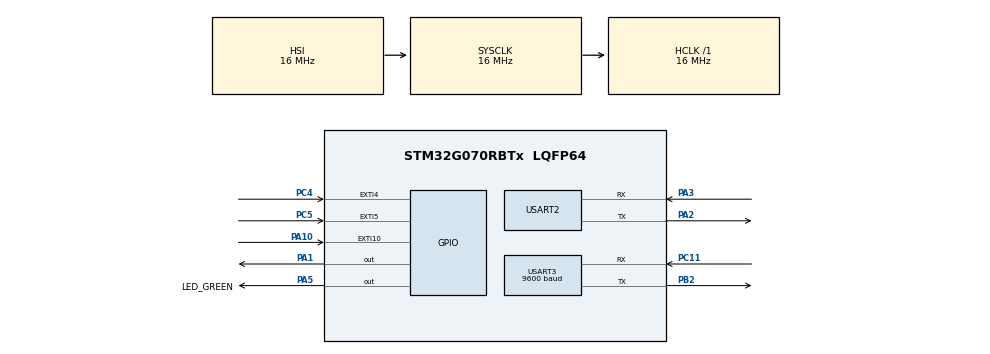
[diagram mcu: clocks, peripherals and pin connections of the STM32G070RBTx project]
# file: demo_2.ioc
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Mcu.Family=STM32G0
Mcu.Name=STM32G070RBTx
Mcu.Package=LQFP64
NVIC.EXTI4_15_IRQn=true\:0\:0\:false\:false\:true\:true\:true
PA1.Signal=GPIO_Output
PA10.GPIO_ModeDefaultEXTI=GPIO_MODE_IT_RISING_FALLING
PA10.GPIO_PuPd=GPIO_PULLUP
PA10.Signal=GPXTI10
PA13.GPIO_Label=TMS
PA13.Mode=Serial_Wire
PA13.Signal=SYS_SWDIO
PA14-BOOT0.GPIO_Label=TCK
PA14-BOOT0.Mode=Serial_Wire
PA14-BOOT0.Signal=SYS_SWCLK
PA2.GPIO_PuPd=GPIO_PULLUP
PA2.Mode=Asynchronous
PA2.Signal=USART2_TX
PA3.GPIO_PuPd=GPIO_PULLUP
PA3.Mode=Asynchronous
PA3.Signal=USART2_RX
PA5.GPIO_Label=LED_GREEN
PA5.GPIO_Speed=GPIO_SPEED_FREQ_HIGH
PA5.Signal=GPIO_Output
PB2.Mode=Asynchronous
PB2.Signal=USART3_TX
PC11.Mode=Asynchronous
PC11.Signal=USART3_RX
PC13.Mode=SYS_WakeUp1
PC13.Signal=SYS_WKUP2
PC14-OSC32_IN\ (PC14).Mode=LSE-External-Oscillator
PC14-OSC32_IN\ (PC14).Signal=RCC_OSC32_IN
PC15-OSC32_OUT\ (PC15).Mode=LSE-External-Oscillator
PC15-OSC32_OUT\ (PC15).Signal=RCC_OSC32_OUT
PC4.GPIO_ModeDefaultEXTI=GPIO_MODE_IT_FALLING
PC4.GPIO_PuPd=GPIO_PULLUP
PC4.Signal=GPXTI4
PC5.GPIO_ModeDefaultEXTI=GPIO_MODE_IT_RISING_FALLING
PC5.GPIO_PuPd=GPIO_PULLUP
PC5.Signal=GPXTI5
PF0-OSC_IN\ (PF0).GPIO_Label=MCO
PF0-OSC_IN\ (PF0).Mode=HSE-External-Clock-Source
PF0-OSC_IN\ (PF0).Signal=RCC_OSC_IN
ProjectManager.HeapSize=0x200
ProjectManager.StackSize=0x400
ProjectManager.TargetToolchain=STM32CubeIDE
RCC.AHBFreq_Value=16000000
RCC.CortexFreq_Value=16000000
RCC.EXTERNAL_CLOCK_VALUE=12288000
RCC.HCLKFreq_Value=16000000
RCC.HSE_VALUE=8000000
RCC.HSI_VALUE=16000000
RCC.SYSCLKFreq_VALUE=16000000
RCC.VCOOutputFreq_Value=128000000
USART2.VirtualMode-Asynchronous=VM_ASYNC
USART2.WordLength=WORDLENGTH_8B
USART3.BaudRate=9600
USART3.VirtualMode-Asynchronous=VM_ASYNC
VP_SYS_VS_DBSignals.Mode=DisableDeadBatterySignals
board=NUCLEO-G070RB

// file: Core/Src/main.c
/* USER CODE BEGIN Header */
/**
  ******************************************************************************
  * @file           : main.c
  * @brief          : Main program body
  ******************************************************************************
  * @attention
  *
  * <h2><center>&copy; Copyright (c) 2020 STMicroelectronics.
  * All rights reserved.</center></h2>
  *
  * This software component is licensed by ST under BSD 3-Clause license,
  * the "License"; You may not use this file except in compliance with the
  * License. You may obtain a copy of the License at:
  *                        opensource.org/licenses/BSD-3-Clause
  *
  ******************************************************************************
  */
/* USER CODE END Header */
#include "main.h"

/* USER CODE BEGIN Includes */
#include "stdio.h"
#include "string.h"
/* USER CODE END Includes */

UART_HandleTypeDef huart2;
UART_HandleTypeDef huart3;

void SystemClock_Config(void);
static void MX_GPIO_Init(void);
static void MX_USART2_UART_Init(void);
static void MX_USART3_UART_Init(void);

int main(void)
{

  /* MCU Configuration--------------------------------------------------------*/

  /* Reset of all peripherals, Initializes the Flash interface and the Systick. */
  HAL_Init();

  /* Configure the system clock */
  SystemClock_Config();

  /* Initialize all configured peripherals */
  MX_GPIO_Init();
  MX_USART2_UART_Init();
  MX_USART3_UART_Init();
  /* USER CODE BEGIN 2 */
  char *msg = "Hello world!\r\n";
  char *Llow = "0";
  char *Lhigh = "75\r\n";

  /* USER CODE END 2 */

  /* Infinite loop */
  /* USER CODE BEGIN WHILE */
  while (1)
  {

//	  if (HAL_GPIO_ReadPin(GPIOB, GPIO_PIN_0)==0){
//		  HAL_UART_Transmit(&huart2, (uint8_t*)Llow, strlen(Llow), 1);
//		  HAL_Delay(100);
//	  }
//	  else if (HAL_GPIO_ReadPin(GPIOB, GPIO_PIN_0)==1){
//		  HAL_UART_Transmit(&huart2, (uint8_t*)Lhigh, strlen(Lhigh), 1);
//		  HAL_Delay(100);
//	  }

    /* USER CODE END WHILE */

  }
}

void SystemClock_Config(void)
{
  RCC_OscInitTypeDef RCC_OscInitStruct = {0};
  RCC_ClkInitTypeDef RCC_ClkInitStruct = {0};
  RCC_PeriphCLKInitTypeDef PeriphClkInit = {0};

  /** Configure the main internal regulator output voltage
  */
  HAL_PWREx_ControlVoltageScaling(PWR_REGULATOR_VOLTAGE_SCALE1);
  /** Initializes the RCC Oscillators according to the specified parameters
  * in the RCC_OscInitTypeDef structure.
  */
  RCC_OscInitStruct.OscillatorType = RCC_OSCILLATORTYPE_HSI;
  RCC_OscInitStruct.HSIState = RCC_HSI_ON;
  RCC_OscInitStruct.HSIDiv = RCC_HSI_DIV1;
  RCC_OscInitStruct.HSICalibrationValue = RCC_HSICALIBRATION_DEFAULT;
  RCC_OscInitStruct.PLL.PLLState = RCC_PLL_NONE;
  if (HAL_RCC_OscConfig(&RCC_OscInitStruct) != HAL_OK)
  {
    Error_Handler();
  }
  /** Initializes the CPU, AHB and APB buses clocks
  */
  RCC_ClkInitStruct.ClockType = RCC_CLOCKTYPE_HCLK|RCC_CLOCKTYPE_SYSCLK
                              |RCC_CLOCKTYPE_PCLK1;
  RCC_ClkInitStruct.SYSCLKSource = RCC_SYSCLKSOURCE_HSI;
  RCC_ClkInitStruct.AHBCLKDivider = RCC_SYSCLK_DIV1;
  RCC_ClkInitStruct.APB1CLKDivider = RCC_HCLK_DIV1;

  if (HAL_RCC_ClockConfig(&RCC_ClkInitStruct, FLASH_LATENCY_0) != HAL_OK)
  {
    Error_Handler();
  }
  /** Initializes the peripherals clocks
  */
  PeriphClkInit.PeriphClockSelection = RCC_PERIPHCLK_USART2;
  PeriphClkInit.Usart2ClockSelection = RCC_USART2CLKSOURCE_PCLK1;
  if (HAL_RCCEx_PeriphCLKConfig(&PeriphClkInit) != HAL_OK)
  {
    Error_Handler();
  }
}

static void MX_USART2_UART_Init(void)
{

  huart2.Instance = USART2;
  huart2.Init.BaudRate = 115200;
  huart2.Init.WordLength = UART_WORDLENGTH_8B;
  huart2.Init.StopBits = UART_STOPBITS_1;
  huart2.Init.Parity = UART_PARITY_NONE;
  huart2.Init.Mode = UART_MODE_TX_RX;
  huart2.Init.HwFlowCtl = UART_HWCONTROL_NONE;
  huart2.Init.OverSampling = UART_OVERSAMPLING_16;
  huart2.Init.OneBitSampling = UART_ONE_BIT_SAMPLE_DISABLE;
  huart2.Init.ClockPrescaler = UART_PRESCALER_DIV1;
  huart2.AdvancedInit.AdvFeatureInit = UART_ADVFEATURE_NO_INIT;
  if (HAL_UART_Init(&huart2) != HAL_OK)
  {
    Error_Handler();
  }
  if (HAL_UARTEx_SetTxFifoThreshold(&huart2, UART_TXFIFO_THRESHOLD_1_8) != HAL_OK)
  {
    Error_Handler();
  }
  if (HAL_UARTEx_SetRxFifoThreshold(&huart2, UART_RXFIFO_THRESHOLD_1_8) != HAL_OK)
  {
    Error_Handler();
  }
  if (HAL_UARTEx_DisableFifoMode(&huart2) != HAL_OK)
  {
    Error_Handler();
  }

}

static void MX_USART3_UART_Init(void)
{

  huart3.Instance = USART3;
  huart3.Init.BaudRate = 9600;
  huart3.Init.WordLength = UART_WORDLENGTH_8B;
  huart3.Init.StopBits = UART_STOPBITS_1;
  huart3.Init.Parity = UART_PARITY_NONE;
  huart3.Init.Mode = UART_MODE_TX_RX;
  huart3.Init.HwFlowCtl = UART_HWCONTROL_NONE;
  huart3.Init.OverSampling = UART_OVERSAMPLING_16;
  huart3.Init.OneBitSampling = UART_ONE_BIT_SAMPLE_DISABLE;
  huart3.Init.ClockPrescaler = UART_PRESCALER_DIV1;
  huart3.AdvancedInit.AdvFeatureInit = UART_ADVFEATURE_NO_INIT;
  if (HAL_UART_Init(&huart3) != HAL_OK)
  {
    Error_Handler();
  }

}

static void MX_GPIO_Init(void)
{
  GPIO_InitTypeDef GPIO_InitStruct = {0};

  /* GPIO Ports Clock Enable */
  __HAL_RCC_GPIOC_CLK_ENABLE();
  __HAL_RCC_GPIOF_CLK_ENABLE();
  __HAL_RCC_GPIOA_CLK_ENABLE();
  __HAL_RCC_GPIOB_CLK_ENABLE();

  /*Configure GPIO pin Output Level */
  HAL_GPIO_WritePin(GPIOA, GPIO_PIN_1|GPIO_PIN_4|LED_GREEN_Pin, GPIO_PIN_RESET);

  /*Configure GPIO pins : PA1 PA4 */
  GPIO_InitStruct.Pin = GPIO_PIN_1|GPIO_PIN_4;
  GPIO_InitStruct.Mode = GPIO_MODE_OUTPUT_PP;
  GPIO_InitStruct.Pull = GPIO_NOPULL;
  GPIO_InitStruct.Speed = GPIO_SPEED_FREQ_LOW;
  HAL_GPIO_Init(GPIOA, &GPIO_InitStruct);

  /*Configure GPIO pin : LED_GREEN_Pin */
  GPIO_InitStruct.Pin = LED_GREEN_Pin;
  GPIO_InitStruct.Mode = GPIO_MODE_OUTPUT_PP;
  GPIO_InitStruct.Pull = GPIO_NOPULL;
  GPIO_InitStruct.Speed = GPIO_SPEED_FREQ_HIGH;
  HAL_GPIO_Init(LED_GREEN_GPIO_Port, &GPIO_InitStruct);

  /*Configure GPIO pin : PC4 */
  GPIO_InitStruct.Pin = GPIO_PIN_4;
  GPIO_InitStruct.Mode = GPIO_MODE_IT_FALLING;
  GPIO_InitStruct.Pull = GPIO_PULLUP;
  HAL_GPIO_Init(GPIOC, &GPIO_InitStruct);

  /*Configure GPIO pin : PC5 */
  GPIO_InitStruct.Pin = GPIO_PIN_5;
  GPIO_InitStruct.Mode = GPIO_MODE_IT_RISING_FALLING;
  GPIO_InitStruct.Pull = GPIO_PULLUP;
  HAL_GPIO_Init(GPIOC, &GPIO_InitStruct);

  /*Configure GPIO pin : PB0 */
  GPIO_InitStruct.Pin = GPIO_PIN_0;
  GPIO_InitStruct.Mode = GPIO_MODE_INPUT;
  GPIO_InitStruct.Pull = GPIO_NOPULL;
  HAL_GPIO_Init(GPIOB, &GPIO_InitStruct);

  /*Configure GPIO pin : PA10 */
  GPIO_InitStruct.Pin = GPIO_PIN_10;
  GPIO_InitStruct.Mode = GPIO_MODE_IT_RISING_FALLING;
  GPIO_InitStruct.Pull = GPIO_PULLUP;
  HAL_GPIO_Init(GPIOA, &GPIO_InitStruct);

  /* EXTI interrupt init*/
  HAL_NVIC_SetPriority(EXTI4_15_IRQn, 0, 0);
  HAL_NVIC_EnableIRQ(EXTI4_15_IRQn);

}

void Error_Handler(void)
{
}

/************************ (C) COPYRIGHT STMicroelectronics *****END OF FILE****/
